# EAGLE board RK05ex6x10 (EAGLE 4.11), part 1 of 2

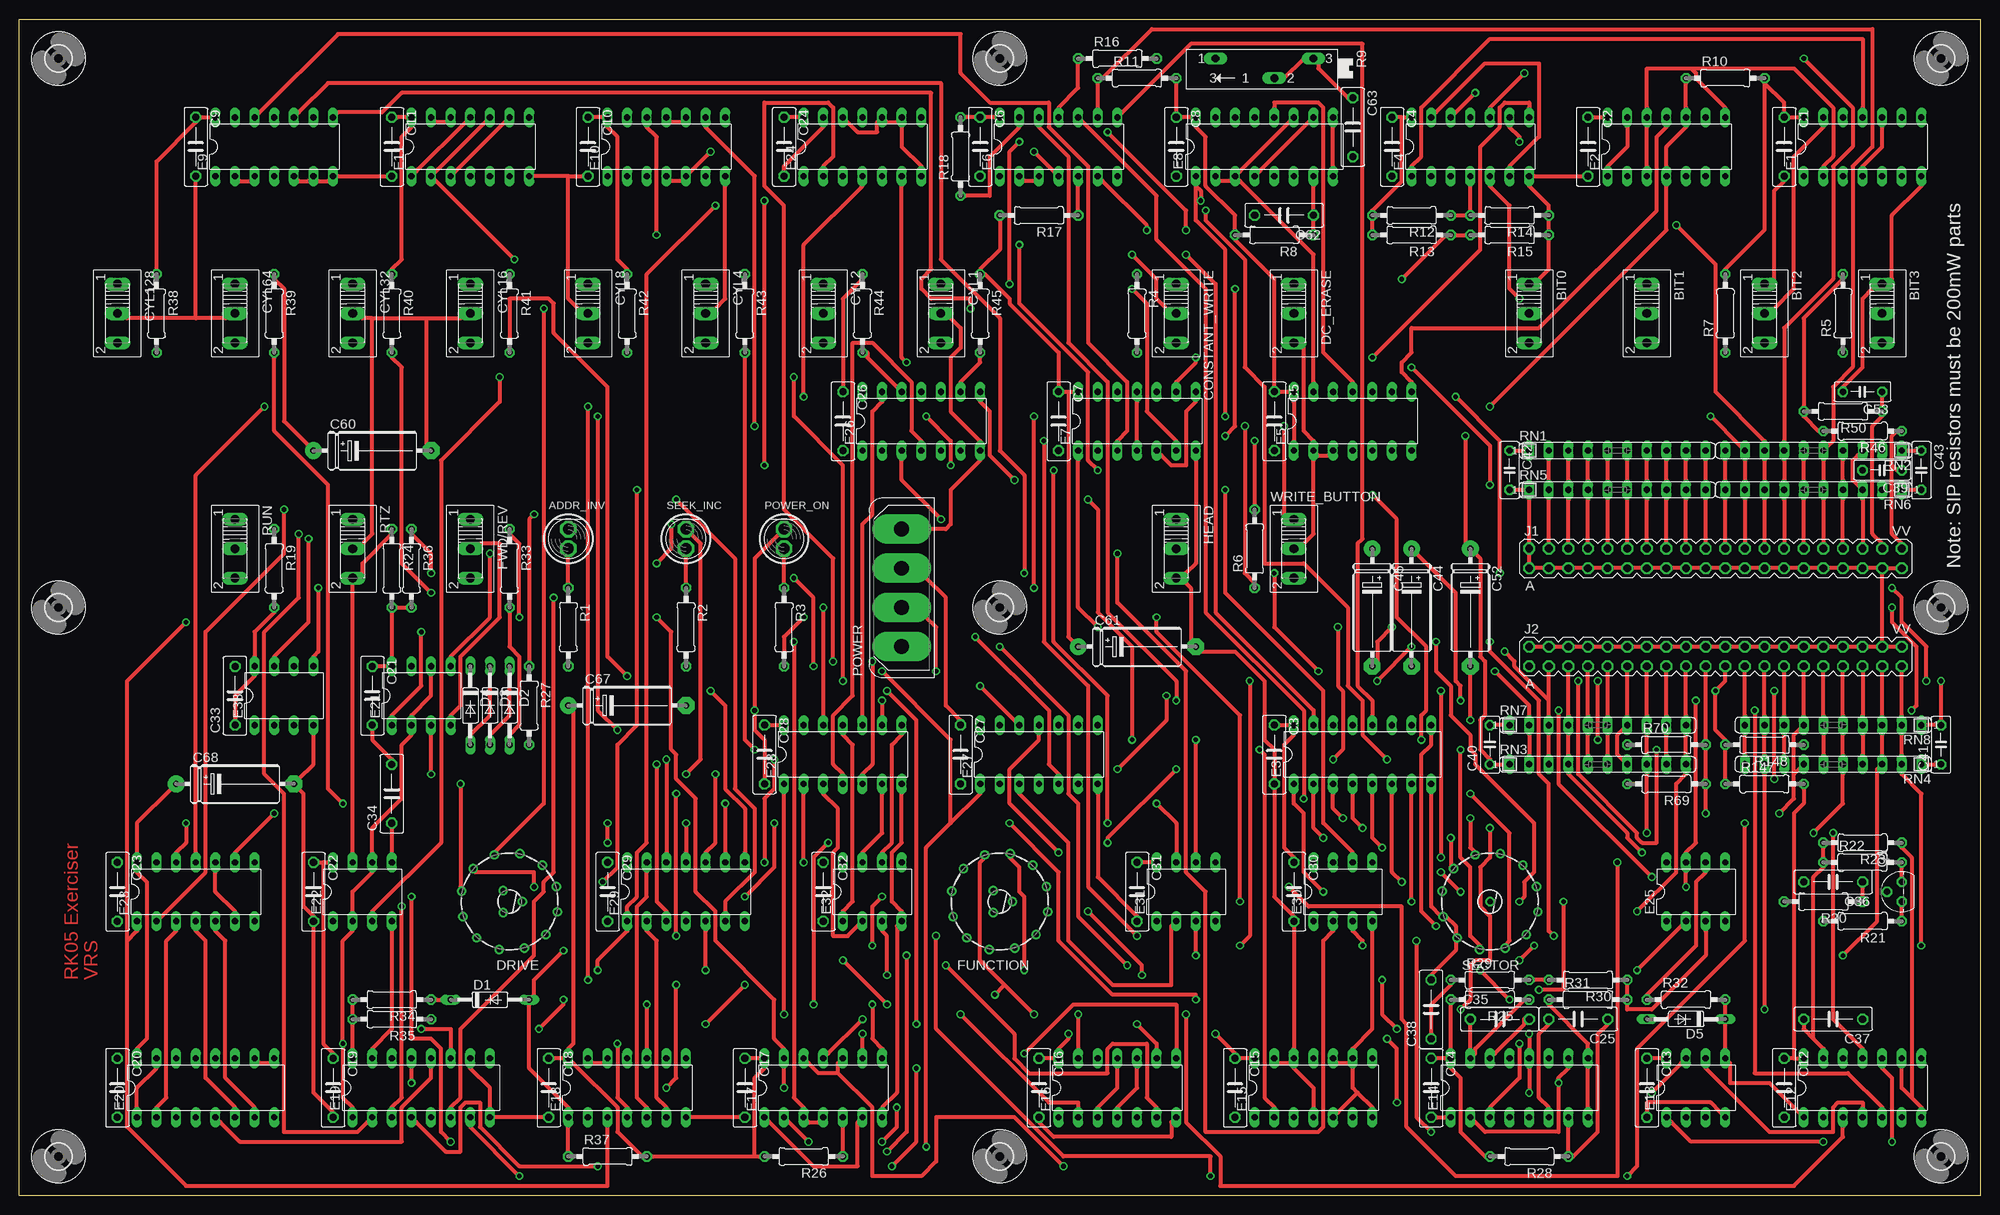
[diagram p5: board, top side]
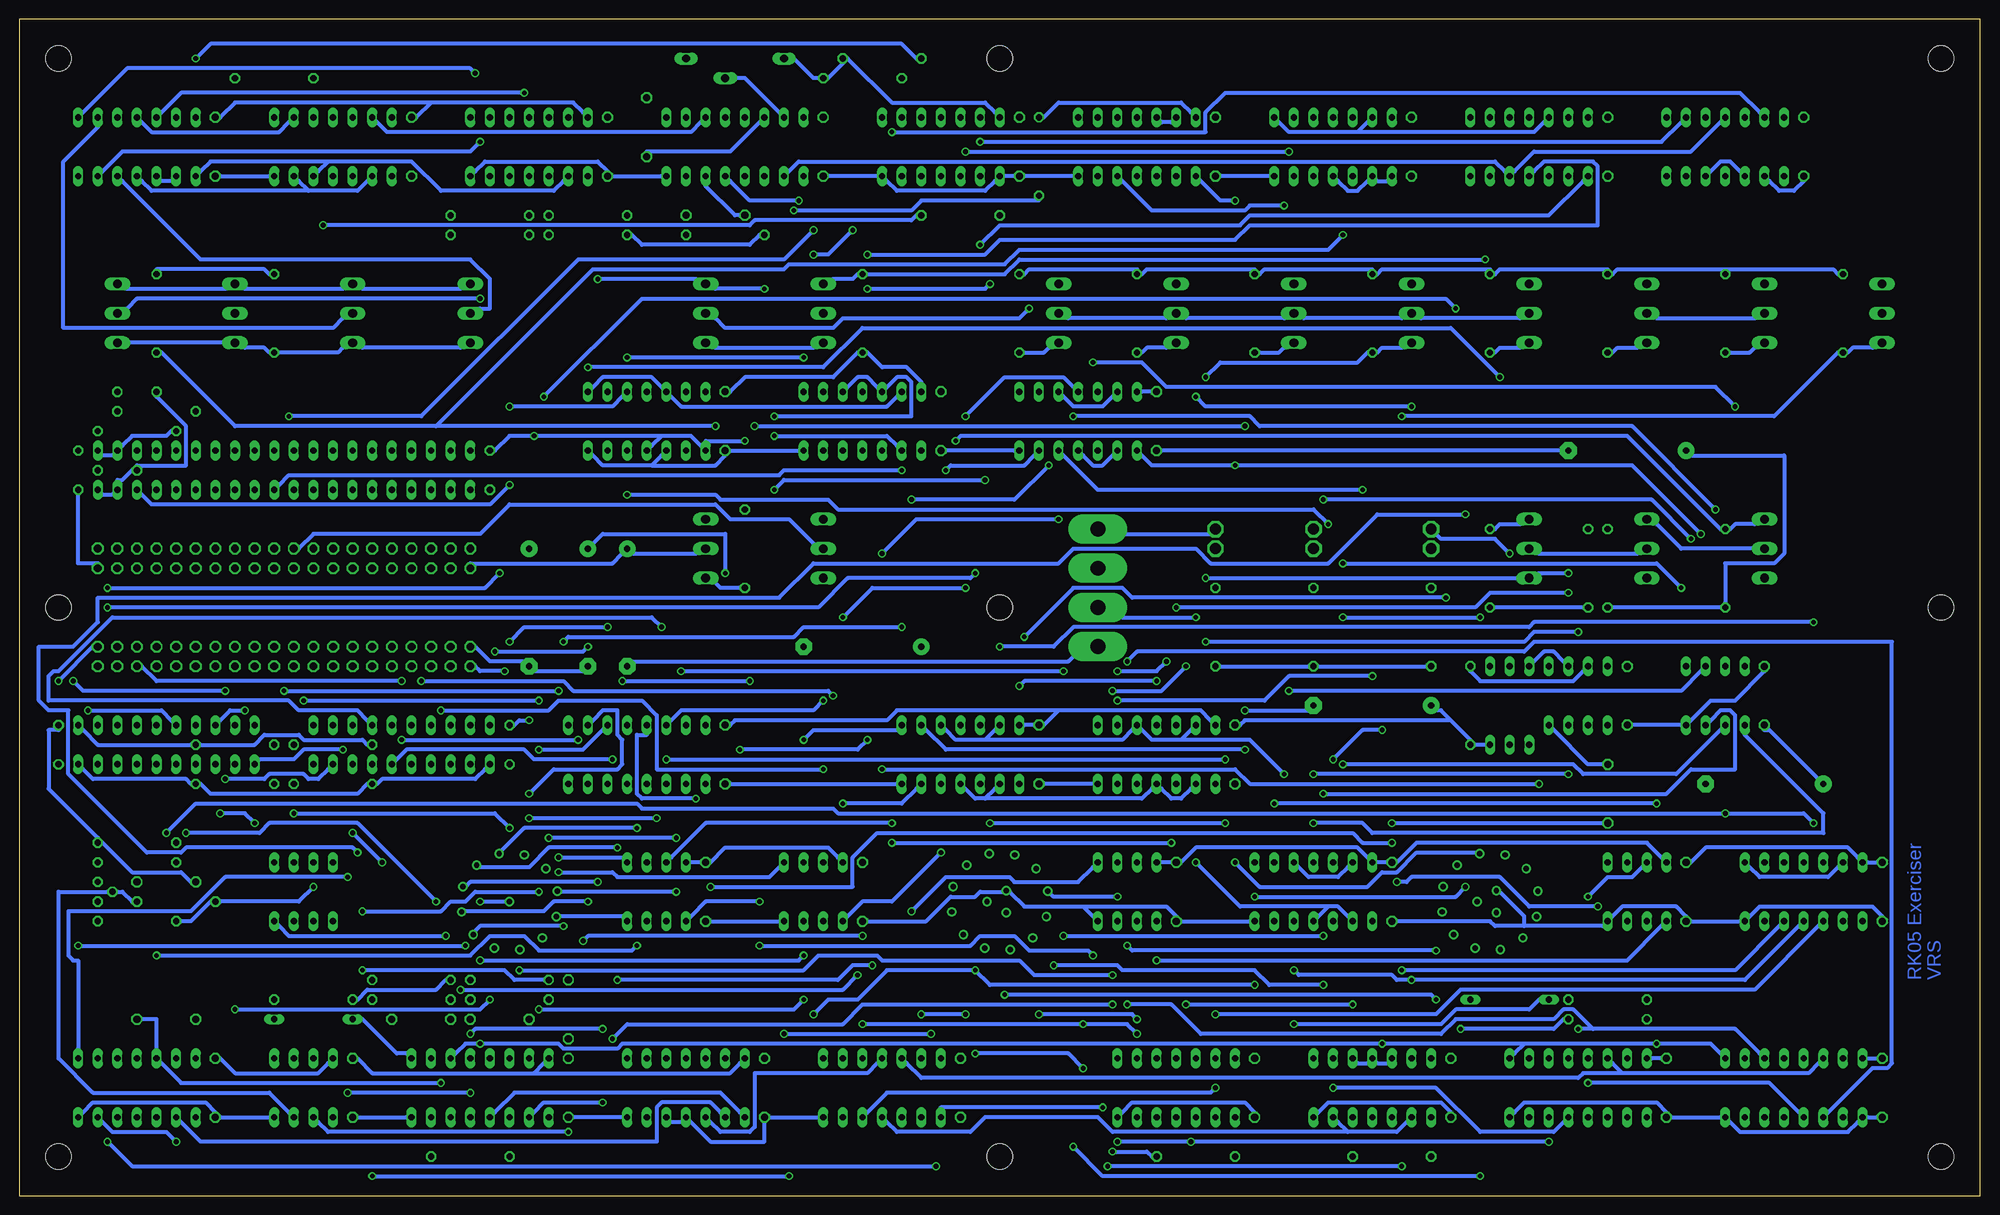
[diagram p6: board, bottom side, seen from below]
Size 254 x 152.4 mm. Coordinates in mm from the lower left corner, seen from the top.
Outline: 0,0 0,152.4 254,152.4 254,0 0,0
Copper layers (1*16): Top 0.035mm / dielectric 1.5mm / Bottom 0.035mm
Design rules "10mils": minimum track width 10mil, minimum drill 24mil, track to track 10mil, track to pad 10mil, pad to pad 10mil, via to via 10mil, smd to smd 10mil, copper to edge 25mil, drill to drill 10mil, minimum pad ring 10mil, minimum via ring 8mil, stop-mask expansion 0mil, vias tented up to drill 0mil, thermal gap 10mil
Net classes: 0 default: width 0.508 mm, drill 0.279 mm

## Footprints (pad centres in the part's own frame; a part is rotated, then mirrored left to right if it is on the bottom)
BULB = drill 1.422 octagon: A 0,0; B 0,2.54
255SB = drill 1.118 long: 1 -3.81,0; 2 0,0; 3 3.81,0
C075-032X103 = drill 0.914 octagon: 1 -3.81,0; 2 3.81,0
C050-025X075 = drill 0.813 octagon: 1 -2.54,0; 2 2.54,0
E15-5 = drill 0.813 pad 2.159 round: + -7.62,0 | drill 0.813 pad 2.159 octagon: - 7.62,0
DO35-10 = drill 0.813 long: A 5.08,0; C -5.08,0
DO35Z10 = drill 0.813 long: A 5.08,0; C -5.08,0
50-3POLE30 = drill 0.7 pad 1.2 round: 1 6.207,-1.342; 2 4.704,-4.265; 3 1.941,-6.046; 4 -1.342,-6.207; 5 -4.265,-4.704; 6 -6.046,-1.941; 7 -6.207,1.342; 8 -4.704,4.265; 9 -1.941,6.046; 10 1.342,6.207; 11 4.265,4.704; 12 6.046,1.941; C1 0.825,-1.429; C2 -1.65,0; C3 0.825,1.429
DIL14 = drill 0.813 long: 1 -7.62,-3.81; 2 -5.08,-3.81; 3 -2.54,-3.81; 4 0,-3.81; 5 2.54,-3.81; 6 5.08,-3.81; 7 7.62,-3.81; 8 7.62,3.81; 9 5.08,3.81; 10 2.54,3.81; 11 0,3.81; 12 -2.54,3.81; 13 -5.08,3.81; 14 -7.62,3.81
DIL16 = drill 0.813 long: 1 -8.89,-3.81; 2 -6.35,-3.81; 3 -3.81,-3.81; 4 -1.27,-3.81; 5 1.27,-3.81; 6 3.81,-3.81; 7 6.35,-3.81; 8 8.89,-3.81; 9 8.89,3.81; 10 6.35,3.81; 11 3.81,3.81; 12 1.27,3.81; 13 -1.27,3.81; 14 -3.81,3.81; 15 -6.35,3.81; 16 -8.89,3.81
DIL08 = drill 0.813 long: 1 -3.81,-3.81; 2 -1.27,-3.81; 3 1.27,-3.81; 4 3.81,-3.81; 5 3.81,3.81; 6 1.27,3.81; 7 -1.27,3.81; 8 -3.81,3.81
DEC40PINV = drill 1.016 octagon: A -24.13,-1.27; AA 3.81,-1.27; B -24.13,1.27; BB 3.81,1.27; C -21.59,-1.27; CC 6.35,-1.27; D -21.59,1.27; DD 6.35,1.27; E -19.05,-1.27; EE 8.89,-1.27; F -19.05,1.27; FF 8.89,1.27; H -16.51,-1.27; HH 11.43,-1.27; J -16.51,1.27; JJ 11.43,1.27; K -13.97,-1.27; KK 13.97,-1.27; L -13.97,1.27; LL 13.97,1.27; M -11.43,-1.27; MM 16.51,-1.27; N -11.43,1.27; NN 16.51,1.27; P -8.89,-1.27; PP 19.05,-1.27; R -8.89,1.27; RR 19.05,1.27; S -6.35,-1.27; SS 21.59,-1.27; T -6.35,1.27; TT 21.59,1.27; U -3.81,-1.27; UU 24.13,-1.27; V -3.81,1.27; VV 24.13,1.27; W -1.27,-1.27; X -1.27,1.27; Y 1.27,-1.27; Z 1.27,1.27
FLOPPY-4 = drill 1.93 pad 3.81 long: 1 7.62,0; 2 2.54,0; 3 -2.54,0; 4 -7.62,0
TO92E = drill 0.813 octagon: B1 -1.27,0; B2 1.27,0; E 0,1.905
0207/10 = drill 0.813 octagon: 1 -5.08,0; 2 5.08,0
SP19L = drill 1.016 long: A 5.715,-1.27; E -6.985,-1.27; S -1.905,1.27
SIL10 = drill 0.813 long: 1 -11.43,0; 2 -8.89,0; 3 -6.35,0; 4 -3.81,0; 5 -1.27,0; 6 1.27,0; 7 3.81,0; 8 6.35,0; 9 8.89,0; 10 11.43,0
50-1POLE30 = drill 0.7 pad 1.2 round: 1 6.207,-1.342; 2 4.704,-4.265; 3 1.941,-6.046; 4 -1.342,-6.207; 5 -4.265,-4.704; 6 -6.046,-1.941; 7 -6.207,1.342; 8 -4.704,4.265; 9 -1.941,6.046; 10 1.342,6.207; 11 4.265,4.704; 12 6.046,1.941; C 0,0
3,3 = hole 3.3: 0,0

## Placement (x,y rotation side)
ADDR_INV  [BULB]  71.12,83.82 0 top
BIT0  [255SB]  195.58,114.3 270 top
BIT1  [255SB]  210.82,114.3 270 top
BIT2  [255SB]  226.06,114.3 270 top
BIT3  [255SB]  241.3,114.3 270 top
C1  .01uf  [C075-032X103]  228.6,135.89 270 top
C2  .01uf  [C075-032X103]  203.2,135.89 270 top
C3  .01uf  [C075-032X103]  162.56,57.15 270 top
C4  .01uf  [C075-032X103]  177.8,135.89 270 top
C5  .01uf  [C075-032X103]  162.56,100.33 270 top
C6  .01uf  [C075-032X103]  124.46,135.89 270 top
C7  .01uf  [C075-032X103]  134.62,100.33 270 top
C8  .01uf  [C075-032X103]  149.86,135.89 270 top
C9  .01uf  [C075-032X103]  22.86,135.89 270 top
C10  .01uf  [C075-032X103]  73.66,135.89 270 top
C11  .01uf  [C075-032X103]  48.26,135.89 270 top
C12  .01uf  [C075-032X103]  228.6,13.97 270 top
C13  .01uf  [C075-032X103]  210.82,13.97 270 top
C14  .01uf  [C075-032X103]  182.88,13.97 270 top
C15  .01uf  [C075-032X103]  157.48,13.97 270 top
C16  .01uf  [C075-032X103]  132.08,13.97 270 top
C17  .01uf  [C075-032X103]  93.98,13.97 270 top
C18  .01uf  [C075-032X103]  68.58,13.97 270 top
C19  .01uf  [C075-032X103]  40.64,13.97 270 top
C20  .01uf  [C075-032X103]  12.7,13.97 270 top
C21  .01uf  [C075-032X103]  45.72,64.77 270 top
C22  .01uf  [C075-032X103]  38.1,39.37 270 top
C23  .01uf  [C075-032X103]  12.7,39.37 270 top
C24  .01uf  [C075-032X103]  99.06,135.89 270 top
C25  470pf  [C075-032X103]  201.93,22.86 180 top
C26  .01uf  [C075-032X103]  106.68,100.33 270 top
C27  .01uf  [C075-032X103]  121.92,57.15 270 top
C28  .01uf  [C075-032X103]  96.52,57.15 270 top
C29  .01uf  [C075-032X103]  76.2,39.37 270 top
C30  .01uf  [C075-032X103]  165.1,39.37 270 top
C31  .01uf  [C075-032X103]  144.78,39.37 270 top
C32  .01uf  [C075-032X103]  104.14,39.37 270 top
C33  .01uf  [C075-032X103]  27.94,64.77 90 top
C34  .001uf  [C075-032X103]  48.26,52.07 90 top
C35  470pf  [C075-032X103]  191.77,22.86 0 top
C36  .033uf  [C075-032X103]  234.95,40.64 180 top
C37  .001uf  [C075-032X103]  234.95,22.86 180 top
C38  100pf  [C075-032X103]  182.88,24.13 90 top
C39  .001  [C050-025X075]  241.3,93.98 180 top
C40  .22uf  [C050-025X075]  190.5,58.42 90 top
C41  .22uf  [C050-025X075]  248.92,58.42 90 top
C42  .22uf  [C050-025X075]  193.04,93.98 270 top
C43  .22uf  [C050-025X075]  246.38,93.98 270 top
C44  6.8uf  [E15-5]  180.34,76.2 270 top
C45  6.8uf  [E15-5]  175.26,76.2 270 top
C52  39uf  [E15-5]  187.96,76.2 270 top
C53  .001  [C050-025X075]  238.76,104.14 180 top
C60  6.8uf  [E15-5]  45.72,96.52 0 top
C61  6.8uf  [E15-5]  144.78,71.12 0 top
C62  27pf  [C075-032X103]  163.83,127 180 top
C63  47pf  [C075-032X103]  172.72,138.43 270 top
C67  6.8uf  [E15-5]  78.74,63.5 0 top
C68  6.8uf  [E15-5]  27.94,53.34 0 top
CONSTANT_WRITE  [255SB]  149.86,114.3 270 top
CYL1  [255SB]  119.38,114.3 270 top
CYL2  [255SB]  104.14,114.3 270 top
CYL4  [255SB]  88.9,114.3 270 top
CYL8  [255SB]  73.66,114.3 270 top
CYL16  [255SB]  58.42,114.3 270 top
CYL32  [255SB]  43.18,114.3 270 top
CYL64  [255SB]  27.94,114.3 270 top
CYL128  [255SB]  12.7,114.3 270 top
D1  D664  [DO35-10]  60.96,25.4 0 top
D2  D664  [DO35-10]  63.5,63.5 270 top
D3  D664  [DO35-10]  60.96,63.5 270 top
D4  D664  [DO35-10]  58.42,63.5 270 top
D5  1N746  [DO35Z10]  215.9,22.86 180 top
DC_ERASE  [255SB]  165.1,114.3 270 top
DRIVE  50-3POLE30  [50-3POLE30]  63.5,38.1 180 top
E1  74LS10N  [DIL14]  238.76,135.89 0 top
E2  74LS74N  [DIL14]  213.36,135.89 0 top
E3  74LS42N  [DIL16]  173.99,57.15 0 top
E4  74LS20N  [DIL14]  187.96,135.89 0 top
E5  74LS74N  [DIL14]  172.72,100.33 0 top
E6  74LS04N  [DIL14]  134.62,135.89 0 top
E7  74LS00N  [DIL14]  144.78,100.33 0 top
E8  74123N  [DIL16]  161.29,135.89 0 top
E9  DS8881N  [DIL14]  33.02,135.89 0 top
E10  74LS00N  [DIL14]  83.82,135.89 0 top
E11  74LS74N  [DIL14]  58.42,135.89 0 top
E12  74LS04N  [DIL14]  238.76,13.97 0 top
E13  DS75451N  [DIL08]  217.17,13.97 0 top
E14  74123N  [DIL16]  194.31,13.97 0 top
E15  74LS00N  [DIL14]  167.64,13.97 0 top
E16  74LS10N  [DIL14]  142.24,13.97 0 top
E17  74LS00N  [DIL14]  104.14,13.97 0 top
E18  74LS74N  [DIL14]  78.74,13.97 0 top
E19  74LS193N  [DIL16]  52.07,13.97 0 top
E20  74LS193N  [DIL16]  24.13,13.97 0 top
E21  DS75451N  [DIL08]  52.07,64.77 0 top
E22  DS75451N  [DIL08]  44.45,39.37 0 top
E23  74LS10N  [DIL14]  22.86,39.37 0 top
E24  74LS20N  [DIL14]  109.22,135.89 0 top
E25  LM741P  [DIL08]  217.17,39.37 0 top
E26  74LS00N  [DIL14]  116.84,100.33 0 top
E27  74LS00N  [DIL14]  132.08,57.15 0 top
E28  74LS00N  [DIL14]  106.68,57.15 0 top
E29  74LS00N  [DIL14]  86.36,39.37 0 top
E30  DS75451N  [DIL08]  171.45,39.37 0 top
E31  DS75451N  [DIL08]  151.13,39.37 0 top
E32  DS75451N  [DIL08]  110.49,39.37 0 top
E33  DS75451N  [DIL08]  34.29,64.77 0 top
FUNCTION  50-3POLE30  [50-3POLE30]  127,38.1 180 top
FWD/REV  [255SB]  58.42,83.82 270 top
HEAD  [255SB]  149.86,83.82 270 top
IC1  OPA1013P  [DIL08]  not placed on the board
J1  DEC40PINSV  [DEC40PINV]  219.71,82.55 0 top
J2  DEC40PINSV  [DEC40PINV]  219.71,69.85 0 top
POWER  [FLOPPY-4]  114.3,78.74 90 top
POWER_ON  [BULB]  99.06,83.82 0 top
Q1  2N4894  [TO92E]  243.84,39.37 90 top
R1  0ohm  [0207/10]  71.12,73.66 270 top
R2  0ohm  [0207/10]  86.36,73.66 270 top
R3  0ohm  [0207/10]  99.06,73.66 270 top
R4  1K  [0207/10]  144.78,114.3 270 top
R5  56K  [0207/10]  236.22,114.3 90 top
R6  56K  [0207/10]  160.02,83.82 90 top
R7  1K  [0207/10]  220.98,114.3 90 top
R8  5.6k  [0207/10]  162.56,124.46 180 top
R9  10K  [SP19L]  160.66,146.05 180 top
R10  1K  [0207/10]  220.98,144.78 0 top
R11  1K  [0207/10]  144.78,144.78 0 top
R12  330  [0207/10]  180.34,127 180 top
R13  330  [0207/10]  180.34,124.46 180 top
R14  750  [0207/10]  193.04,127 180 top
R15  750  [0207/10]  193.04,124.46 180 top
R16  1K  [0207/10]  142.24,147.32 0 top
R17  1K  [0207/10]  132.08,127 180 top
R18  1K  [0207/10]  121.92,134.62 90 top
R19  1K  [0207/10]  33.02,81.28 270 top
R20  470K  [0207/10]  233.68,38.1 180 top
R21  330  [0207/10]  238.76,35.56 180 top
R22  120  [0207/10]  238.76,43.18 0 top
R23  68  [0207/10]  238.76,45.72 180 top
R24  1K  [0207/10]  48.26,81.28 270 top
R25  10K  [0207/10]  190.5,25.4 180 top
R26  1K  [0207/10]  101.6,5.08 180 top
R27  1K  [0207/10]  66.04,63.5 270 top
R28  22K  [0207/10]  195.58,5.08 180 top
R29  100K  [0207/10]  190.5,27.94 0 top
R30  100K  [0207/10]  203.2,27.94 180 top
R31  1M  [0207/10]  203.2,25.4 0 top
R32  1K  [0207/10]  215.9,25.4 0 top
R33  1K  [0207/10]  63.5,81.28 270 top
R34  1K  [0207/10]  48.26,25.4 180 top
R35  1K  [0207/10]  48.26,22.86 180 top
R36  1K  [0207/10]  50.8,81.28 270 top
R37  1K  [0207/10]  76.2,5.08 0 top
R38  1K  [0207/10]  17.78,114.3 270 top
R39  1K  [0207/10]  33.02,114.3 270 top
R40  1K  [0207/10]  48.26,114.3 270 top
R41  1K  [0207/10]  63.5,114.3 270 top
R42  1K  [0207/10]  78.74,114.3 270 top
R43  1K  [0207/10]  93.98,114.3 270 top
R44  1K  [0207/10]  109.22,114.3 270 top
R45  1K  [0207/10]  124.46,114.3 270 top
R46  390  [0207/10]  238.76,99.06 180 top
R50  390  [0207/10]  236.22,101.6 180 top
R69  180  [0207/10]  213.36,53.34 180 top
R70  390  [0207/10]  213.36,58.42 0 top
R147  180  [0207/10]  226.06,53.34 0 top
R148  390  [0207/10]  226.06,58.42 180 top
RN1  180  [SIL10]  207.01,96.52 0 top
RN2  180  [SIL10]  232.41,96.52 180 top
RN3  180  [SIL10]  204.47,55.88 0 top
RN4  180  [SIL10]  234.95,55.88 180 top
RN5  390  [SIL10]  207.01,91.44 0 top
RN6  390  [SIL10]  232.41,91.44 180 top
RN7  390  [SIL10]  204.47,60.96 0 top
RN8  390  [SIL10]  234.95,60.96 180 top
RTZ  [255SB]  43.18,83.82 270 top
RUN  [255SB]  27.94,83.82 270 top
SECTOR  50-1POLE30  [50-1POLE30]  190.5,38.1 180 top
SEEK_INC  [BULB]  86.36,83.82 0 top
U$1  [3,3]  5.08,147.32 0 top
U$2  [3,3]  5.08,5.08 0 top
U$3  [3,3]  5.08,76.2 0 top
U$4  [3,3]  248.92,147.32 0 top
U$5  [3,3]  248.92,5.08 0 top
U$6  [3,3]  248.92,76.2 0 top
U$7  [3,3]  127,147.32 0 top
U$8  [3,3]  127,5.08 0 top
U$9  [3,3]  127,76.2 0 top
WRITE_BUTTON  MOM  [255SB]  165.1,83.82 270 top

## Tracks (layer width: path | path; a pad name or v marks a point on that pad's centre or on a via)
0BIT  (via drill 0.61)
  Top 0.508: v194.31,136.53 194.31,137.16 193.04,138.43 E4.9
  Bottom 0.508: v194.31,136.53 195.58,135.25 240.66,135.25 243.21,132.72 E1.6
1.44MHZ
  Top 0.508: E5.11 172.72,105.41 168.91,109.22 168.91,140.97 168.28,141.6 162.56,141.6 162.56,140.97 E8.12
1BIT  (via drill 0.61)
  Top 0.508: v194.94,145.41 190.5,140.97 E4.10
  Bottom 0.508: v194.94,145.41 195.58,146.05 240.03,146.05 245.75,140.34 E1.8
1L
  Top 0.508: E2.11 213.36,138.43 212.09,137.16 212.09,127.64 196.85,112.39 180.34,112.39 180.34,109.22 179.07,107.95 179.07,106.68 180.34,105.41 E5.8
  Bottom 0.508: E7.13 140.34,103.5 141.6,102.23 168.28,102.23 169.54,103.5 E5.12 170.81,104.78 172.09,106.05 178.44,106.05 179.71,104.78 E5.8
2.88MHZ
  Top 0.508: E8.4 160.66,132.72 167,139.06 E8.10
2BIT  (via drill 0.61)
  Top 0.508: v188.59,142.88 186.06,140.34 E4.12
  Bottom 0.508: v188.59,142.88 233.04,142.88 235.59,140.34 E1.12
2H
  Top 0.508: E4.1 180.34,133.35 181.61,134.62 181.61,140.97 190.5,149.86 238.76,149.86 238.76,140.97 E1.11
  Bottom 0.508: E2.9 219.07,139.06 220.34,137.79 236.85,137.79 238.12,139.06 E1.11
2L
  Top 0.508: E2.3 210.82,133.35 210.82,138.43 E2.12 210.82,140.97 210.82,146.05 216.53,146.05 | 216.53,146.05 217.17,145.41 217.17,144.78 220.98,140.97 E2.8 | 216.53,146.05 229.87,146.05 234.95,140.97 234.95,134.62 233.68,133.35 E1.2
  Bottom 0.508: E1.2 234.31,131.44 235.59,131.44 E1.3
3BIT
  Top 0.508: E4.13 183.51,140.34 189.87,146.69 196.85,146.69 196.85,137.16 193.04,133.35 E4.6
4H
  Bottom 0.508: 214,133.99 203.2,133.99 199.39,130.18 184.78,130.18 183.51,131.44 E4.2 | 214,133.99 215.26,132.72 E2.5 | 214,133.99 229.24,133.99 230.5,132.72 E1.1
4L
  Top 0.508: E1.4 238.76,133.35 241.3,135.89 241.3,138.43 E1.10
  Bottom 0.508: 216.53,130.18 210.19,130.18 208.91,131.44 E2.2 | 216.53,130.18 217.81,131.44 E2.6 | 216.53,130.18 236.85,130.18 238.12,131.44 E1.4
202_DETECT_L  (via drill 0.61)
  Top 0.508: v31.75,102.23 22.86,93.34 22.86,44.45 E23.11 | v114.94,107.95 114.3,108.58 114.3,130.81 E24.6
  Bottom 0.508: v31.75,102.23 34.29,104.78 105.41,104.78 108.58,107.95 v114.94,107.95
+3V  (via drill 0.61)
  Top 0.508: E21.6 53.34,67.31 53.34,64.77 50.8,62.23 E21.2 50.8,59.69 49.53,58.42 49.53,51.44 45.72,47.62 45.72,44.45 E22.6 45.72,41.91 43.18,39.37 43.18,36.83 E22.2 43.18,34.29 41.91,33.02 v41.91,19.68 41.91,12.7 43.18,11.43 E19.1 | v194.31,19.68 194.31,15.24 190.5,11.43 E14.3 | E20.10 31.11,17.14 32.38,17.14 E20.9 | v77.47,19.68 77.47,12.7 78.74,11.43 E18.4
  Bottom 0.508: D4.C 57.78,69.22 56.52,70.48 55.24,70.48 53.98,69.22 E21.6 | E14.11 197.49,18.41 196.22,19.68 v194.31,19.68 184.15,19.68 183.51,19.05 176.53,19.05 175.9,19.68 v77.47,19.68 59.05,19.68 | 59.05,19.68 60.33,18.41 E19.9 | 59.05,19.68 v41.91,19.68 34.92,19.68 33.66,18.41 E20.9
+3VA  (via drill 0.61)
  Top 0.508: R15.2 187.32,124.46 186.06,124.46 R13.1 184.78,124.46 v179.07,118.75 | v156.21,98.42 157.48,99.69 v157.48,117.47
  Bottom 0.508: v156.21,98.42 141.6,98.42 140.34,97.16 E7.2 | v157.48,117.47 163.83,117.47 DC_ERASE.1 166.37,118.75 v179.07,118.75
+3VB
  Top 0.508: R12.1 186.06,127 187.32,127 R14.2 187.96,127.64 187.96,130.81 E4.4
+3VC  (via drill 0.61)
  Top 0.508: E11.10 60.33,139.06 53.98,132.72 E11.2 53.98,131.44 v64.14,121.28
  Bottom 0.508: CONSTANT_WRITE.1 148.59,118.75 146.05,118.75 145.41,119.38 R4.1 144.15,119.38 126.36,119.38 124.46,121.28 v64.14,121.28
+15V  (via drill 0.61)
  Top 0.508: v101.6,74.93 99.06,72.39 99.06,69.22 R3.2 | v215.9,40.01 215.9,41.91 E25.7 215.9,44.45 217.17,45.72 v217.17,64.14 | v186.69,64.14 186.69,66.04 186.06,66.67 186.06,78.11 180.97,83.19 C44.+ | v118.75,67.94 118.75,73.66 117.47,74.93 POWER.3 | v168.28,67.94 162.56,73.66 v162.56,80.64
  Bottom 0.508: R1.2 71.75,68.58 85.72,68.58 R2.2 87,68.58 98.42,68.58 R3.2 | v101.6,74.93 111.12,74.93 POWER.3 | R21.2 233.04,35.56 231.78,35.56 229.24,38.1 R20.2 227.97,38.1 217.81,38.1 v215.9,40.01 | v217.17,64.14 v186.69,64.14 | v168.28,67.94 v118.75,67.94 | v162.56,80.64 162.56,85.72 178.44,85.72 179.71,84.45 C44.+
-15V  (via drill 0.61)
  Top 0.508: v198.75,33.66 198.12,34.29 198.12,53.34 196.85,54.61 196.85,64.14 190.5,70.48 v190.5,71.75 | v177.8,73.66 175.9,71.75 175.9,69.22 C45.-
  Bottom 0.508: v198.75,33.66 219.07,33.66 220.34,34.92 E25.4 | v190.5,71.75 188.59,73.66 v177.8,73.66 | POWER.4 117.47,69.85 118.11,69.22 174.62,69.22 C45.-
ADDR_COUNTER_1  (via drill 0.61)
  Top 0.508: v49.53,37.47 49.53,12.7 48.26,11.43 E19.3 | v75.56,40.64 77.47,42.55 77.47,58.42 80.01,60.96 v80.01,91.44
  Bottom 0.508: v49.53,37.47 58.42,37.47 62.23,41.27 73.66,41.27 74.3,40.64 v75.56,40.64 | v80.01,91.44 114.3,91.44 118.75,95.89 E26.5
ADDR_COUNTER_2  (via drill 0.61)
  Top 0.508: v36.2,85.72 36.2,77.47 31.75,73.03 31.75,54.61 34.29,52.07 34.29,8.26 43.81,8.26 45.09,9.53 E19.2 | v96.52,94.61 v96.52,128.91
  Bottom 0.508: v36.2,85.72 45.09,94.61 v96.52,94.61 107.31,94.61 108.58,95.89 E26.1 | v96.52,128.91 98.42,128.91 100.97,131.44 E24.1
ADDR_COUNTER_4  (via drill 0.61)
  Top 0.508: v69.22,77.47 69.22,41.91 67.94,40.64 67.94,39.37 66.67,38.1 66.67,31.11 57.15,21.59 57.15,12.7 55.88,11.43 E19.6 | v123.83,72.39 133.35,62.87 133.35,55.88 134.62,54.61 E27.5
  Bottom 0.508: v69.22,77.47 109.86,77.47 111.12,78.74 117.47,78.74 v123.83,72.39
ADDR_COUNTER_8  (via drill 0.61)
  Top 0.508: v64.77,2.54 58.42,8.89 E19.7 | v117.47,6.35 117.47,45.09 120.65,48.26 | 120.65,48.26 124.46,52.07 E27.1 | v105.41,69.22 105.41,82.55 99.06,88.9 99.06,128.27 96.52,130.81 96.52,141.6 104.78,141.6 105.41,140.97 105.41,134.62 104.14,133.35 E24.2 | v111.76,67.94 120.65,59.05 120.65,48.26
  Bottom 0.508: v64.77,2.54 113.67,2.54 v117.47,6.35 | v105.41,69.22 106.68,67.94 v111.76,67.94
ADDR_COUNTER_16  (via drill 0.61)
  Top 0.508: v110.49,69.22 110.49,55.88 109.22,54.61 E28.5
  Bottom 0.508: v110.49,69.22 109.22,70.48 59.05,70.48 57.78,71.75 11.43,71.75 11.43,17.14 12.06,16.51 13.97,16.51 19.68,10.79 E20.3
ADDR_COUNTER_32  (via drill 0.61)
  Top 0.508: E20.2 17.78,11.43 19.05,12.7 19.05,33.02 20.32,34.29 E23.3 | v99.06,23.5 99.06,52.07 E28.1
  Bottom 0.508: v99.06,23.5 70.48,23.5 67.31,26.67 29.21,26.67 20.95,34.92 E23.3
ADDR_COUNTER_64  (via drill 0.61)
  Top 0.508: E20.6 27.94,11.43 24.13,15.24 24.13,33.02 22.86,34.29 E23.4 | v88.9,29.21 88.9,34.29 E29.5 | v101.6,103.5 101.6,123.19 109.22,130.81 E24.4 | v73.66,27.94 v73.66,102.23
  Bottom 0.508: v88.9,29.21 88.27,28.57 76.2,28.57 75.56,27.94 v73.66,27.94 30.48,27.94 23.5,34.92 E23.4 | v101.6,103.5 100.33,102.23 v73.66,102.23
ADDR_COUNTER_128  (via drill 0.61)
  Top 0.508: E20.7 30.48,11.43 26.67,15.24 26.67,33.02 25.4,34.29 E23.5 | v74.93,29.21 74.93,30.48 78.74,34.29 E29.1 78.74,36.83 78.74,37.47 80.01,38.73 80.01,44.45 81.28,45.72 81.28,119.38 v90.17,128.27
  Bottom 0.508: v74.93,29.21 31.75,29.21 26.04,34.92 E23.5 | v90.17,128.27 94.61,128.27 95.25,127.64 107.31,127.64 111.12,131.44 E24.5
ADDR_SOURCE_H  (via drill 0.61)
  Top 0.508: E18.5 81.28,11.43 80.01,12.7 80.01,37.47 81.28,38.73 81.28,41.91 E29.13 | E26.13 111.76,102.87 110.49,101.6 110.49,88.27 109.22,87 109.22,62.23 E28.10 | v90.17,54.61 90.17,45.72 88.9,44.45 E29.10
  Bottom 0.508: E29.10 88.27,42.55 87,41.27 83.19,41.27 81.92,42.55 E29.13 | E26.13 112.39,103.5 113.67,102.23 117.47,102.23 118.75,103.5 E26.10 | 103.5,59.05 102.23,60.33 E28.13 | 103.5,59.05 107.31,59.05 108.58,60.33 E28.10 109.86,60.33 111.12,59.05 128.91,59.05 | 128.91,59.05 127.64,60.33 E27.13 | 128.91,59.05 132.72,59.05 133.99,60.33 E27.10 | v90.17,54.61 94.61,59.05 103.5,59.05
ADDR_SOURCE_L  (via drill 0.61)
  Top 0.508: E26.4 116.84,97.79 115.57,99.06 115.57,105.41 110.49,110.49 107.95,110.49 107.95,64.77 105.41,62.23 105.41,55.88 106.68,54.61 E28.4 | E16.4 142.24,11.43 144.78,13.97 144.78,16.51 E16.10 | E29.2 81.28,34.29 82.55,33.02 82.55,12.7 83.82,11.43 E18.6 | v101.6,43.18 101.6,52.07 E28.2
  Bottom 0.508: E26.2 112.39,95.89 113.67,94.61 114.94,94.61 116.2,95.89 E26.4 | E28.2 102.23,52.7 103.5,51.44 104.78,51.44 106.05,52.7 E28.4 107.31,52.7 108.58,51.44 128.91,51.44 | 128.91,51.44 127.64,52.7 E27.2 | 128.91,51.44 130.18,51.44 131.44,52.7 E27.4 | 84.45,37.47 83.19,37.47 81.92,36.2 E29.2 | 84.45,37.47 85.72,36.2 E29.4 | 81.92,8.26 75.56,8.26 74.3,9.53 E18.2 | 81.92,8.26 83.19,9.53 E18.6 | 81.92,8.26 112.39,8.26 114.3,10.16 128.91,10.16 130.81,8.26 140.34,8.26 141.6,9.53 E16.4 | v101.6,43.18 95.89,37.47 84.45,37.47
ADDRESS_INVALID_L  (via drill 0.61)
  Top 0.508: v60.96,83.19 60.96,74.93 55.88,69.85 E21.5
  Bottom 0.508: v60.96,83.19 62.87,85.09 69.85,85.09 70.48,85.72 ADDR_INV.B
BIT_0L
  Bottom 0.508: E1.5 240.66,131.44 230.5,121.28 195.58,121.28 193.04,118.75 193.04,114.94 194.31,114.94 BIT0.2
BIT_1L
  Bottom 0.508: E1.9 243.84,138.43 248.28,133.99 248.28,112.39 213.36,112.39 212.09,113.67 BIT1.2
BIT_2L
  Top 0.508: E1.13 233.68,138.43 229.87,134.62 229.87,117.47 227.33,114.94 BIT2.2
BIT_3L  (via drill 0.61)
  Top 0.508: v194.31,116.2 193.04,117.47 193.04,128.27 190.5,130.81 E4.5
  Bottom 0.508: v194.31,116.2 238.76,116.2 240.03,114.94 BIT3.2
BUS_AC_LO_L
  Top 0.508: 242.57,94.61 243.21,93.98 C39.1 | 242.57,94.61 242.57,98.42 243.21,99.06 R46.1 | 242.57,94.61 242.57,85.72 243.84,84.45 J1.VV
BUS_ADDR_ACCEPTED_L
  Top 0.508: RN3.5 203.2,57.15 203.2,59.69 RN7.5 203.2,62.23 203.2,67.94 J2.H
BUS_ADDRESS_INVALID_L  (via drill 0.61)
  Top 0.508: R26.1 106.68,5.71 106.68,8.89 E17.5 | RN3.3 198.12,57.15 198.12,59.69 RN7.3 198.12,62.23 198.12,64.14 | 198.12,64.14 198.12,67.94 J2.C | v112.39,5.71 114.94,8.26 v114.94,31.11 | v158.12,32.38 159.38,33.66 v159.38,66.67 | v180.34,71.12 v175.9,66.67 | v192.41,70.48 193.68,69.22 193.68,68.58 198.12,64.14
  Bottom 0.508: v112.39,5.71 107.95,5.71 107.31,5.08 R26.1 | v114.94,31.11 115.57,31.75 123.19,31.75 125.09,33.66 129.54,33.66 130.81,32.38 v158.12,32.38 | v175.9,66.67 v159.38,66.67 | v180.34,71.12 180.97,70.48 v192.41,70.48
BUS_CA_00_L  (via drill 0.61)
  Top 0.508: R147.1 220.98,53.98 220.98,57.78 R148.2 220.98,59.05 219.71,60.33 v219.71,65.41 220.98,66.67 220.98,67.94 J2.Y | v184.15,65.41 v184.15,43.81
  Bottom 0.508: v184.15,43.81 175.9,43.81 E30.5 | v219.71,65.41 v184.15,65.41
BUS_CA_01_L  (via drill 0.61)
  Top 0.508: v173.99,32.38 173.99,33.02 172.72,34.29 E30.3 | v236.22,31.11 240.66,35.56 240.66,55.24 RN4.3 241.3,57.15 241.3,59.69 RN8.3 241.3,62.23 241.3,67.94 J2.SS
  Bottom 0.508: v173.99,32.38 174.62,31.75 186.69,31.75 188.59,33.66 193.04,33.66 195.58,31.11 v236.22,31.11
BUS_CA_02_L  (via drill 0.61)
  Top 0.508: v186.69,39.37 v184.15,41.91 | v209.55,36.83 214.63,41.91 214.63,53.34 215.9,54.61 RN3.10 215.9,57.15 215.9,59.69 RN7.10 215.9,62.23 215.9,67.94 J2.U
  Bottom 0.508: v184.15,41.91 177.16,41.91 176.53,41.27 156.84,41.27 155.57,42.55 E31.5 | v186.69,39.37 194.94,39.37 196.22,38.1 198.12,38.1 199.39,36.83 v209.55,36.83
BUS_CA_03_L  (via drill 0.61)
  Top 0.508: v152.4,31.11 152.4,34.29 E31.3 | v196.22,32.38 v194.31,30.48 | v246.38,32.38 246.38,52.07 243.84,54.61 RN4.2 243.84,57.15 243.84,59.69 RN8.2 243.84,62.23 243.84,67.94 J2.UU
  Bottom 0.508: v152.4,31.11 153.03,30.48 v194.31,30.48 | v246.38,32.38 v196.22,32.38
BUS_CA_04_L  (via drill 0.61)
  Top 0.508: v138.43,36.83 145.41,29.84 v145.41,28.57 | v196.85,26.67 200.03,26.67 v200.03,38.1 | v232.41,46.99 236.22,50.8 236.22,54.61 RN4.5 236.22,57.15 236.22,59.69 RN8.5 236.22,62.23 236.22,67.94 J2.MM
  Bottom 0.508: v138.43,36.83 133.99,41.27 125.73,41.27 125.09,40.64 116.84,40.64 114.94,42.55 E32.5 | v145.41,28.57 147.32,26.67 v196.85,26.67 | v200.03,38.1 210.19,48.26 221.62,48.26 222.88,46.99 v232.41,46.99
BUS_CA_05_L  (via drill 0.61)
  Top 0.508: v112.39,28.57 112.39,33.66 111.76,34.29 E32.3 | v193.04,25.4 v189.23,29.21 | v226.06,24.13 226.06,54.61 RN4.9 226.06,57.15 226.06,59.69 RN8.9 226.06,62.23 226.06,67.94 J2.CC
  Bottom 0.508: v112.39,28.57 122.56,28.57 124.46,30.48 142.24,30.48 142.88,31.11 150.5,31.11 152.4,29.21 v189.23,29.21 | v193.04,25.4 194.31,24.13 v226.06,24.13
BUS_CA_06_L  (via drill 0.61)
  Top 0.508: RN4.4 238.76,57.15 238.76,59.69 RN8.4 238.76,62.23 238.76,67.94 J2.PP | v38.73,78.74 38.73,70.48 38.1,69.85 E33.5 | v82.55,81.92 84.45,83.82 v84.45,87 | v175.26,90.81 178.44,87.63 178.44,74.93 182.25,71.12 182.25,62.87 181.61,62.23 v181.61,59.05 | v204.47,59.05 v204.47,66.67
  Bottom 0.508: v38.73,78.74 41.91,81.92 v82.55,81.92 | v84.45,87 86.36,88.9 147.96,88.9 149.22,90.17 163.19,90.17 163.83,90.81 v175.26,90.81 | v204.47,59.05 v181.61,59.05 | v204.47,66.67 236.22,66.67 238.12,68.58 J2.PP
BUS_CA_07_L  (via drill 0.61)
  Top 0.508: J2.HH 231.14,67.94 231.14,62.23 RN8.7 230.5,60.33 229.87,59.69 229.87,54.61 | v85.09,33.66 v85.09,52.07 | v118.75,33.66 118.75,21.59 135.25,5.08 154.31,5.08 v154.31,2.54 | v208.28,2.54 209.55,3.81 209.55,19.05 223.52,33.02 v223.52,48.26 | v227.97,49.53 229.87,51.44 229.87,54.61 | 229.87,54.61 230.5,55.24 RN4.7
  Bottom 0.508: v85.09,52.07 40.64,52.07 37.47,55.24 31.75,55.24 31.75,62.23 32.38,62.87 33.66,62.87 34.92,61.59 E33.3 | v118.75,33.66 v85.09,33.66 | v208.28,2.54 v154.31,2.54 | v223.52,48.26 224.79,49.53 v227.97,49.53
BUS_DATA&CLOCK_L  (via drill 0.61)
  Top 0.508: RN4.6 233.68,57.15 233.68,59.69 RN8.6 233.68,62.23 233.68,67.94 J2.KK | v130.18,80.64 130.18,93.34 127,96.52 127,113.67 119.38,121.28 119.38,144.15 40.01,144.15 36.2,140.34 E9.10 | v242.57,76.2 242.57,74.3 245.75,71.12 245.75,63.5 v245.11,62.87
  Bottom 0.508: v130.18,80.64 130.81,80.01 146.69,80.01 150.5,76.2 v242.57,76.2 | v245.11,62.87 235.59,62.87 234.31,61.59 RN8.6
BUS_DC_LO_L
  Top 0.508: C53.1 241.3,103.5 241.3,102.23 R50.1 241.3,100.97 240.03,99.69 240.03,85.72 241.3,84.45 J1.TT
BUS_FILE_READY
  Top 0.508: RN1.9 215.9,95.25 215.9,92.71 RN5.9 215.9,90.17 215.9,84.45 J1.V
BUS_HIGH_DENSITY_L
  Top 0.508: RN1.6 208.28,95.25 208.28,92.71 RN5.6 208.28,90.17 208.28,84.45 J1.N
BUS_INDEX_L  (via drill 0.61)
  Top 0.508: RN2.10 220.98,95.25 220.98,92.71 RN6.10 220.98,90.17 220.98,84.45 J1.Z | E11.1 51.44,132.72 57.78,139.06 E11.11 | v139.7,93.98 138.43,95.25 138.43,106.68 129.54,115.57 v129.54,123.19
  Bottom 0.508: v139.7,93.98 154.94,93.98 155.57,93.34 219.07,93.34 220.34,92.08 RN6.10 | v129.54,123.19 127,125.73 95.89,125.73 94.61,127 55.88,127 51.44,131.44 E11.1
BUS_READ_GATE_L
  Top 0.508: RN1.5 205.74,95.25 205.74,92.71 RN5.5 205.74,90.17 205.74,84.45 J1.L
BUS_RESTORE_L  (via drill 0.61)
  Top 0.508: E22.5 48.26,44.45 48.26,47.62 C34.1 | J2.P 210.82,67.94 210.82,62.23 RN7.8 210.82,59.69 210.82,57.15 RN3.8 210.82,54.61 v210.82,46.99 | v76.2,45.72 v76.2,48.26 | v164.47,40.01 167,37.47 179.07,37.47 179.07,22.86 179.71,22.23 179.71,8.89 186.06,2.54 207.01,2.54 v207.01,43.18
  Bottom 0.508: v76.2,48.26 48.9,48.26 C34.1 | v76.2,45.72 80.01,45.72 81.28,46.99 142.88,46.99 146.05,43.81 146.05,40.01 v164.47,40.01 | v210.82,46.99 v207.01,43.18
BUS_RWS_READY_L  (via drill 0.61)
  Top 0.508: RN4.8 228.6,57.15 228.6,59.69 RN8.8 228.6,62.23 228.6,67.94 J2.EE | v224.79,62.87 224.79,15.88 236.85,15.88 241.3,11.43 E12.5
  Bottom 0.508: v224.79,62.87 226.69,62.87 227.97,61.59 RN8.8
BUS_SECTOR_ADDR_0L  (via drill 0.61)
  Top 0.508: R17.1 137.16,127.64 137.16,130.81 E6.5 | J1.DD 226.06,84.45 226.06,90.17 RN6.8 226.06,92.71 226.06,95.25 RN2.8 226.06,97.79 219.71,104.14 219.71,120.65 v214.63,125.73
  Bottom 0.508: v214.63,125.73 159.38,125.73 158.75,126.36 138.43,126.36 137.79,127 R17.1
BUS_SECTOR_ADDR_1L  (via drill 0.61)
  Top 0.508: RN3.6 205.74,57.15 205.74,59.69 RN7.6 205.74,62.23 205.74,67.94 J2.K | R18.1 122.56,129.54 125.73,129.54 125.73,134.62 129.54,138.43 E6.13 | v177.16,56.52 173.99,59.69 173.99,64.14 172.09,66.04 172.09,76.2 166.37,81.92 161.29,81.92 161.29,104.78 158.75,107.31 158.75,121.28 153.67,126.36 v153.67,127.64
  Bottom 0.508: v177.16,56.52 187.32,56.52 188.59,57.78 203.84,57.78 205.1,56.52 RN3.6 | v153.67,127.64 138.43,127.64 137.16,128.91 121.92,128.91 R18.1
BUS_SECTOR_ADDR_2L  (via drill 0.61)
  Top 0.508: E6.11 134.62,140.97 137.16,143.51 137.16,146.69 R16.1 | J1.FF 228.6,84.45 228.6,90.17 RN6.7 228.6,92.71 228.6,95.25 RN2.7 228.6,97.79 228.6,112.39 234.95,118.75 234.95,133.35 237.49,135.89 237.49,140.97 v231.14,147.32
  Bottom 0.508: v231.14,147.32 229.24,149.22 139.7,149.22 137.79,147.32 R16.1
BUS_SECTOR_ADDR_3L
  Top 0.508: E6.9 139.7,140.97 139.7,144.15 R11.1 140.34,144.78 146.69,151.13 240.03,151.13 240.03,135.89 237.49,133.35 237.49,107.31 234.95,104.78 234.95,97.79 234.31,97.16 RN2.5 233.68,95.25 233.68,92.71 RN6.5 233.68,90.17 233.68,84.45 J1.LL
BUS_SECTOR_PULSE_L
  Top 0.508: RN1.8 213.36,95.25 213.36,92.71 RN5.8 213.36,90.17 213.36,84.45 J1.T
BUS_SEEK_INCOMPLETE_L  (via drill 0.61)
  Top 0.508: J2.E 200.66,67.94 200.66,62.23 RN7.4 200.66,59.69 200.66,57.15 RN3.4 200.66,54.61 208.28,46.99 208.28,46.35 v210.19,44.45 | v66.67,88.27 66.04,87.63 66.04,69.22 R27.1
  Bottom 0.508: E21.7 51.44,67.94 52.7,66.67 64.77,66.67 66.04,67.94 R27.1 | v210.19,44.45 210.82,45.09 232.41,45.09 233.04,44.45 237.49,44.45 247.65,54.61 247.65,62.87 250.19,62.87 251.46,64.14 251.46,71.12 247.01,71.12 243.84,74.3 243.84,77.47 155.57,77.47 151.13,81.92 119.38,81.92 117.47,83.82 101.6,83.82 99.69,81.92 84.45,81.92 78.11,88.27 v66.67,88.27
BUS_STROBE_L  (via drill 0.61)
  Top 0.508: v62.23,106.05 62.23,102.87 54.61,95.25 54.61,45.72 45.72,36.83 E22.3 | v180.34,107.31 190.5,97.16 v190.5,92.08 | RN2.3 238.12,95.89 237.49,95.25 237.49,92.71 238.12,92.08 RN6.3 238.76,90.17 238.76,84.45 J1.RR
  Bottom 0.508: v62.23,106.05 68.58,112.39 144.78,112.39 149.86,107.31 v180.34,107.31 | v190.5,92.08 193.04,89.53 236.85,89.53 238.12,90.81 RN6.3
BUS_WP_SET_L
  Top 0.508: RN1.4 203.2,95.25 203.2,92.71 RN5.4 203.2,90.17 203.2,84.45 J1.J
BUS_WP_STATUS_L
  Top 0.508: RN1.7 210.82,95.25 210.82,92.71 RN5.7 210.82,90.17 210.82,84.45 J1.R
BUS_WRITE_CK
  Top 0.508: RN2.6 231.14,95.25 231.14,92.71 RN6.6 231.14,90.17 231.14,84.45 J1.JJ
BUS_WRITE_GATE_L  (via drill 0.61)
  Top 0.508: v140.97,137.79 151.13,127.64 v151.13,125.09 | v219.07,100.97 222.88,97.16 RN2.9 223.52,95.25 223.52,92.71 RN6.9 223.52,90.17 223.52,84.45 J1.BB
  Bottom 0.508: v140.97,137.79 100.33,137.79 100.33,140.34 97.79,142.88 31.11,142.88 28.57,140.34 E9.13 | v151.13,125.09 154.94,121.28 181.61,121.28 201.93,100.97 v219.07,100.97
CA_SW_1
  Top 0.508: E26.9 121.92,105.41 124.46,107.95 124.46,108.58 R45.2
  Bottom 0.508: CYL1.3 120.65,109.86 121.28,109.22 123.83,109.22 R45.2
CA_SW_2
  Top 0.508: E26.12 113.67,104.78 109.86,108.58 109.86,109.22 R44.2
  Bottom 0.508: R44.2 108.58,109.22 107.95,109.86 105.41,109.86 CYL2.3
CA_SW_4  (via drill 0.61)
  Top 0.508: v95.25,57.78 93.98,59.05 93.98,108.58 R43.2
  Bottom 0.508: v95.25,57.78 133.99,57.78 136.53,60.33 E27.9 | CYL4.3 90.17,109.86 90.81,109.22 93.34,109.22 R43.2
CA_SW_8  (via drill 0.61)
  Top 0.508: v124.46,66.04 128.91,61.59 E27.12 | v106.68,66.67 106.68,94.61 100.33,100.97 v100.33,106.05
  Bottom 0.508: CYL8.3 74.93,109.86 77.47,109.86 78.11,109.22 R42.2 79.38,109.22 80.64,107.95 98.42,107.95 v100.33,106.05 | v124.46,66.04 123.83,66.67 v106.68,66.67
CA_SW_16  (via drill 0.61)
  Top 0.508: v111.76,64.14 111.76,62.23 E28.9 | v78.74,67.31 76.2,69.85 76.2,104.78 69.22,111.76 69.22,115.57 68.58,116.2 63.5,116.2 63.5,109.86 R41.2
  Bottom 0.508: R41.2 62.87,109.22 62.23,109.86 59.69,109.86 CYL16.3 | v111.76,64.14 92.71,64.14 89.53,67.31 v78.74,67.31
CA_SW_32  (via drill 0.61)
  Top 0.508: v104.14,76.2 104.14,62.23 E28.12 | v53.34,78.11 49.53,81.92 49.53,107.31 48.26,108.58 R40.2
  Bottom 0.508: R40.2 47.62,109.22 46.99,109.86 44.45,109.86 CYL32.3 | v104.14,76.2 65.41,76.2 63.5,78.11 v53.34,78.11
CA_SW_64  (via drill 0.61)
  Top 0.508: v91.44,50.8 91.44,44.45 E29.9 | v41.91,50.8 40.01,52.7 40.01,92.08 33.02,99.06 33.02,108.58 R39.2
  Bottom 0.508: v41.91,50.8 v91.44,50.8 | CYL64.3 29.21,109.86 29.84,109.22 32.38,109.22 R39.2
CA_SW_128  (via drill 0.61)
  Top 0.508: v83.82,56.52 83.82,44.45 E29.12 | v77.47,60.33 74.93,62.87 v74.93,100.97
  Bottom 0.508: CYL128.3 13.97,109.86 16.51,109.86 17.14,109.22 R38.2 18.41,109.22 26.67,100.97 v74.93,100.97 | v83.82,56.52 80.01,60.33 v77.47,60.33
CLOCK_H  (via drill 0.61)
  Top 0.508: 152.4,130.81 153.03,130.18 v153.03,128.91 | 152.4,130.81 E8.1 152.4,130.81 | v156.21,100.97 156.21,122.56 152.4,126.36 152.4,130.81
  Bottom 0.508: E7.10 146.69,104.78 145.41,106.05 144.15,106.05 142.88,104.78 E7.12 141.6,104.78 140.34,106.05 139.06,106.05 138.43,105.41 138.43,100.97 v156.21,100.97 | v153.03,128.91 159.38,128.91 161.93,131.44 E8.5
CONSTANT_WRITE_L  (via drill 0.61)
  Top 0.508: v144.15,121.92 147.32,118.75 147.32,116.2 148.59,114.94 CONSTANT_WRITE.2
  Bottom 0.508: v144.15,121.92 128.91,121.92 127,123.83 96.52,123.83 94.61,125.73 49.53,125.73 49.53,133.35 50.16,133.99 56.52,133.99 57.78,132.72 E11.4
DATA_BITS
  Bottom 0.508: BIT0.3 196.85,109.86 209.55,109.86 BIT1.3 212.09,109.86 212.72,109.22 220.34,109.22 R7.1 221.62,109.22 222.25,109.86 224.79,109.86 BIT2.3 227.33,110.49 240.03,110.49 BIT3.3
DC_ERASE  (via drill 0.61)
  Top 0.508: v123.19,114.94 123.19,116.2 118.11,116.2 116.84,117.47 116.84,118.75 118.11,120.02 118.11,142.88 49.53,142.88 46.99,140.34 41.27,140.34 E9.8
  Bottom 0.508: v123.19,114.94 124.46,113.67 147.32,113.67 148.59,112.39 162.56,112.39 163.83,113.67 DC_ERASE.2
FWD_L  (via drill 0.61)
  Top 0.508: v53.34,80.64 53.34,83.19 50.8,85.72 R36.1 | v109.22,20.95 109.22,19.05 E17.9 | v144.78,22.23 147.32,19.68 147.32,19.05 E16.9 | v100.33,80.01 102.87,77.47 v102.87,68.58 | v112.39,65.41 116.2,61.59 v116.2,22.23
  Bottom 0.508: v53.34,80.64 57.15,80.64 FWD/REV.3 59.69,80.01 v100.33,80.01 | v109.22,20.95 110.49,22.23 v116.2,22.23 v144.78,22.23 | v102.87,68.58 106.05,65.41 v112.39,65.41
GND  (via drill 0.61)
  Top 0.508: C53.2 236.22,104.78 238.76,107.31 238.76,116.2 240.03,117.47 BIT3.1 242.57,118.75 242.57,127 246.38,130.81 E1.7 | E8.8 170.18,133.35 170.18,138.43 E8.9 | C2.2 202.56,132.08 196.22,132.08 E4.7 195.58,130.81 198.12,128.27 198.12,127.64 R14.1 198.12,126.36 198.12,125.09 R15.1 198.12,123.83 198.12,120.02 196.85,118.75 BIT0.1 | C1.2 228.6,131.44 227.33,130.18 227.33,118.75 BIT2.1 | RN8.1 247.01,60.96 248.28,60.96 C41.2 248.92,61.59 v248.92,66.67 | 245.11,12.7 243.84,13.97 243.84,16.51 E12.9 | 245.11,12.7 246.38,11.43 E12.7 | E14.8 203.2,11.43 203.2,16.51 E14.9 203.2,19.05 203.2,19.68 198.12,24.77 R31.1 | E13.4 220.34,10.79 219.07,12.06 210.82,12.06 210.82,10.79 C13.2 | 245.11,12.7 245.11,43.81 243.84,45.09 R23.1 | E5.2 168.28,95.89 169.54,95.89 E5.3 | WRITE_BUTTON.2 166.37,84.45 167.64,85.72 167.64,95.25 E5.2 | E7.7 152.4,95.25 152.4,81.92 151.13,80.64 HEAD.3 151.13,79.38 151.76,78.74 151.76,71.75 C61.- 153.03,70.48 157.48,70.48 161.29,66.67 161.29,59.05 162.56,57.78 162.56,53.98 C3.2 162.56,52.7 162.56,38.73 165.1,36.2 C30.2 165.1,34.92 165.1,19.05 E15.12 | DC_ERASE.3 166.37,109.86 166.37,99.06 167.64,97.79 E5.2 | C43.2 245.75,91.44 244.47,91.44 RN6.1 | C42.2 193.68,91.44 194.94,91.44 RN5.1 195.58,90.17 195.58,84.45 J1.B 195.58,83.19 195.58,81.92 J1.A 196.22,81.28 197.49,81.28 J1.C 198.75,81.28 200.03,81.28 J1.E 201.29,81.28 202.56,81.28 J1.H 203.84,81.28 205.1,81.28 J1.K 206.38,81.28 207.65,81.28 J1.M 208.91,81.28 210.19,81.28 J1.P 211.46,81.28 212.72,81.28 J1.S 214,81.28 215.26,81.28 J1.U 216.53,81.28 217.81,81.28 J1.W 219.07,81.28 220.34,81.28 J1.Y 221.62,81.28 222.88,81.28 J1.AA 224.16,81.28 225.43,81.28 J1.CC 226.69,81.28 227.97,81.28 J1.EE 229.24,81.28 230.5,81.28 J1.HH 231.78,81.28 233.04,81.28 J1.KK 234.31,81.28 235.59,81.28 J1.MM 236.85,81.28 238.12,81.28 J1.PP 239.4,81.28 240.66,81.28 J1.SS
  Top 0.508: J1.UU 243.21,81.28 241.94,81.28 J1.SS | C40.2 191.13,60.96 192.41,60.96 RN7.1 | v187.96,61.59 187.96,67.94 C52.- | J2.B 196.22,71.12 197.49,71.12 J2.D 198.75,71.12 200.03,71.12 J2.F 201.29,71.12 202.56,71.12 J2.J 203.84,71.12 205.1,71.12 J2.L 206.38,71.12 207.65,71.12 J2.N 208.91,71.12 210.19,71.12 J2.R 211.46,71.12 212.72,71.12 J2.T 214,71.12 215.26,71.12 J2.V 216.53,71.12 217.81,71.12 J2.X 219.07,71.12 220.34,71.12 J2.Z 221.62,71.12 222.88,71.12 J2.BB 224.16,71.12 225.43,71.12 J2.DD 226.69,71.12 227.97,71.12 J2.FF 229.24,71.12 230.5,71.12 J2.JJ 231.78,71.12 233.04,71.12 J2.LL 234.31,71.12 235.59,71.12 J2.NN 236.85,71.12 238.12,71.12 J2.RR 239.4,71.12 240.66,71.12 J2.TT | J2.VV 243.21,71.12 241.94,71.12 J2.TT | J1.SS 241.3,80.64 241.3,71.75 J2.TT | POWER.1 117.47,86.36 120.02,86.36 120.65,87 120.65,91.44 124.46,95.25 E26.7 124.46,97.79 120.65,101.6 120.65,108.58 121.92,109.86 121.92,112.39 120.65,113.67 CYL1.2 | C28.2 96.52,53.98 96.52,59.05 95.25,60.33 v95.25,62.87 95.25,82.55 98.42,85.72 POWER_ON.B | E24.13 104.14,138.43 99.06,133.35 99.06,132.72 C24.2 | E24.7 116.84,133.35 114.3,135.89 114.3,138.43 E24.9 113.67,139.06 112.39,139.06 E24.10 111.12,139.06 111.12,137.79 108.58,137.79 107.31,139.06 E24.12 | E9.2 28.57,131.44 29.84,131.44 E9.3 | E9.5 36.2,131.44 37.47,131.44 E9.6 38.73,131.44 40.01,131.44 E9.7 41.27,132.08 47.62,132.08 C11.2 | 71.12,132.08 73.03,132.08 C10.2 | 71.12,132.08 66.67,132.08 E11.7 | 22.86,113.67 26.67,113.67 CYL64.2 | 22.86,113.67 13.97,113.67 CYL128.2 | 45.72,113.67 44.45,113.67 CYL32.2 | 45.72,113.67 52.7,113.67
  Top 0.508: 52.7,113.67 57.15,113.67 CYL16.2 | 71.12,132.08 71.12,116.2 72.39,114.94 CYL8.2 | 45.72,113.67 45.72,85.72 44.45,84.45 RTZ.2 | 22.86,113.67 22.86,131.44 C9.2 | 52.7,113.67 52.7,97.16 C60.- | E10.7 91.44,130.81 91.44,116.2 90.17,114.94 CYL4.2 | E19.15 45.72,19.05 48.26,21.59 48.26,34.29 E22.4 | E33.4 38.1,59.69 38.1,55.88 36.2,53.98 C68.- 36.2,52.7 36.83,52.07 36.83,37.47 38.1,36.2 C22.2 38.1,34.92 38.1,13.34 40.64,10.79 C19.2 | C34.2 48.26,56.52 45.72,59.05 45.72,60.33 C21.2 | E20.15 17.78,16.51 15.24,13.97 15.24,11.43 E20.1 | C31.2 144.78,36.2 139.7,41.27 139.7,52.07 E27.7 | E3.8 182.88,52.07 182.88,37.47 184.15,36.2 SECTOR.12 184.78,36.2 186.06,34.92 186.06,33.66 SECTOR.11 186.06,33.02 186.06,31.75 182.88,28.57 C38.2 | C16.2 132.08,9.53 133.99,7.62 149.22,7.62 149.22,9.53 E16.7 | E14.1 184.78,10.16 183.51,10.16 C14.2 | E15.13 163.19,17.14 164.47,17.14 E15.12 | E15.10 170.81,17.14 172.09,17.14 E15.9 | 173.35,13.34 172.72,13.97 172.72,16.51 E15.9 | 173.35,13.34 175.26,11.43 E15.7 | 173.35,13.34 170.81,10.79 E15.5 | E15.12 165.1,16.51 167.64,13.97 167.64,11.43 E15.4 | E30.4 175.26,34.29 175.26,21.59 172.72,19.05 E15.9 | E18.7 87,10.16 93.34,10.16 C17.2 | C18.2 67.94,10.16 61.59,10.16 E19.8 60.96,11.43 60.96,13.97 58.42,16.51 E19.10 | E17.7 111.76,11.43 113.67,13.34 113.67,34.92 E32.4 114.3,36.83 113.03,38.1 113.03,44.45 114.3,45.72 114.3,52.07 E28.7 | FWD/REV.2 59.69,84.45 62.23,84.45 62.23,74.93 57.15,69.85 57.15,63.5 55.88,62.23 E21.4
  Bottom 0.508: E8.8 170.81,132.08 177.16,132.08 C4.2 177.8,132.72 179.07,133.99 193.68,133.99 194.94,132.72 E4.7 | E2.7 221.62,132.08 227.97,132.08 C1.2 | BIT0.1 196.85,117.47 209.55,117.47 BIT1.1 212.09,117.47 224.79,117.47 BIT2.1 227.33,117.47 240.03,117.47 BIT3.1 | C36.2 231.78,40.64 233.04,41.91 239.4,41.91 243.21,45.72 R23.1 243.84,46.35 250.19,52.7 250.19,60.33 248.92,60.33 C41.2 | R70.1 208.91,58.42 209.55,59.05 217.17,59.05 217.81,59.69 222.25,59.69 223.52,58.42 230.5,58.42 R148.1 231.78,58.42 243.84,58.42 245.75,60.33 RN8.1 | E13.4 221.62,10.16 227.97,10.16 C12.2 228.6,10.79 229.87,12.06 244.47,12.06 245.75,10.79 E12.7 | D5.A 209.55,22.86 205.1,18.41 203.84,18.41 E14.9 | C13.2 210.19,10.16 203.84,10.16 E14.8 | CONSTANT_WRITE.3 151.13,109.86 163.83,109.86 DC_ERASE.3 | WRITE_BUTTON.2 166.37,83.19 174.62,83.19 C45.+ 175.9,83.19 177.16,81.92 195.58,81.92 J1.A | E7.7 153.03,96.52 161.93,96.52 C5.2 162.56,95.89 163.83,94.61 172.09,94.61 | 172.09,94.61 178.44,94.61 179.71,95.89 E5.7 | 172.09,94.61 170.81,95.89 E5.3 | RN6.1 243.21,90.81 241.94,90.81 RN6.2 241.3,92.71 240.66,92.71 239.4,93.98 C39.2 238.76,94.61 232.41,94.61 232.41,99.69 236.22,103.5 C53.2 | C43.2 246.38,90.81 246.38,81.92 243.84,81.92 J1.UU | v187.96,61.59 189.23,61.59 189.87,60.96 C40.2 | C44.- 180.97,67.94 187.32,67.94 C52.- 188.59,69.22 193.04,69.22 194.94,71.12 J2.B | v248.92,66.67 244.47,71.12 J2.VV | E26.7 125.09,96.52 133.99,96.52 C7.2 | v95.25,62.87 87,62.87 C67.- | POWER.1 111.12,85.72 99.69,85.72 POWER_ON.B | E24.13 104.78,139.06 106.05,139.06 E24.12 | E10.7 92.08,132.08 98.42,132.08 C24.2
  Bottom 0.508: C8.2 149.22,132.08 142.88,132.08 E6.7 141.6,131.44 140.34,130.18 128.91,130.18 127.64,131.44 E6.1 126.36,132.08 125.09,132.08 C6.2 123.83,132.08 117.47,132.08 E24.7 | C26.2 106.05,96.52 53.98,96.52 C60.- | C9.2 22.86,131.44 24.13,130.18 26.04,130.18 27.3,131.44 E9.2 | E9.3 31.11,132.72 32.38,133.99 33.66,133.99 34.92,132.72 E9.5 | RTZ.2 44.45,83.19 57.15,83.19 FWD/REV.2 | CYL32.2 41.91,113.67 29.21,113.67 CYL64.2 | CYL16.2 59.69,113.67 72.39,113.67 CYL8.2 74.93,113.67 87.63,113.67 CYL4.2 90.17,113.67 102.87,113.67 CYL2.2 105.41,113.67 118.11,113.67 CYL1.2 | 59.05,34.92 59.05,36.2 62.23,39.37 DRIVE.C1 | 59.05,34.92 48.9,34.92 E22.4 47.62,36.2 46.35,37.47 39.37,37.47 38.1,36.2 C22.2 37.47,35.56 31.11,35.56 E23.7 29.84,36.2 28.57,37.47 13.97,37.47 12.7,36.2 C23.2 | 59.05,34.92 62.87,34.92 63.5,35.56 75.56,35.56 C29.2 | E21.4 55.24,60.33 50.8,55.88 48.9,55.88 C34.2 | C21.2 45.09,60.96 38.73,60.96 E33.4 37.47,61.59 34.92,64.14 31.75,64.14 27.94,67.94 C33.2 | C20.2 13.34,10.16 14.61,10.16 E20.1 15.88,9.53 17.14,8.26 31.11,8.26 32.38,9.53 E20.8 33.66,10.16 40.01,10.16 C19.2 40.64,10.79 41.91,12.06 59.05,12.06 60.33,10.79 E19.8 | E27.7 140.34,53.34 161.93,53.34 C3.2 | E30.4 175.9,36.2 184.15,36.2 SECTOR.12 | E16.7 150.5,10.16 156.84,10.16 C15.2 157.48,9.53 157.48,6.99 164.47,6.99 167,9.53 E15.4 168.28,9.53 169.54,9.53 E15.5 | E31.4 155.57,35.56 164.47,35.56 C30.2 | C14.2 182.25,10.16 175.9,10.16 E15.7 | E18.7 85.72,10.79 84.45,12.06 69.85,12.06 68.58,10.79 C18.2 | E29.7 94.61,35.56 103.5,35.56 C32.2 104.14,36.2 105.41,37.47 116.2,37.47 | E28.7 114.94,53.34 121.28,53.34 C27.2
  Bottom 0.508: 116.2,37.47 123.83,37.47 125.73,39.37 FUNCTION.C1 126.36,39.37 129.54,39.37 130.18,38.73 133.35,38.73 136.53,35.56 144.15,35.56 C31.2 | 116.2,37.47 114.94,36.2 E32.4 | C17.2 93.98,10.79 95.25,12.06 109.86,12.06 111.12,10.79 E17.7
HEAD_SELECT_L
  Top 0.508: RN1.10 218.44,95.25 218.44,92.71 RN5.10 218.44,90.17 218.44,84.45 J1.X
  Bottom 0.508: HEAD.2 151.13,84.45 154.31,87.63 161.93,87.63 163.83,89.53 190.5,89.53 194.31,85.72 215.9,85.72 217.81,83.82 J1.X
N$1  (via drill 0.61)
  Top 0.508: v233.68,6.99 216.53,6.99 214,9.53 E13.1
  Bottom 0.508: v233.68,6.99 234.95,8.26 241.94,8.26 243.21,9.53 E12.6
N$2  (via drill 0.61)
  Top 0.508: v129.54,136.53 128.27,135.25 v128.27,118.11 | v144.15,117.47 146.05,115.57 146.05,101.6 149.86,97.79 E7.6
  Bottom 0.508: v129.54,136.53 41.27,136.53 38.73,139.06 E9.9 | v128.27,118.11 128.91,117.47 v144.15,117.47
N$3
  Top 0.508: E11.13 53.98,139.06 55.24,139.06 E11.12
  Bottom 0.508: 80.64,137.79 79.38,139.06 E10.13 | 80.64,137.79 89.53,137.79 90.81,139.06 E10.8 | 80.64,137.79 57.78,137.79 56.52,139.06 E11.12
N$4
  Top 0.508: E10.11 84.45,139.06 85.72,139.06 E10.10
N$5  (via drill 0.61)
  Top 0.508: R10.1 215.9,144.15 215.9,140.97 E2.10 215.9,138.43 213.36,135.89 213.36,133.35 E2.4 213.36,130.81 213.36,125.09 v190.5,102.23
  Bottom 0.508: v190.5,102.23 177.16,102.23 175.9,103.5 E5.10
N$6
  Top 0.508: E7.4 144.78,97.79 144.78,102.87 E7.11
N$7
  Top 0.508: E7.5 147.96,95.89 149.22,94.61 151.13,94.61 151.13,101.6 152.4,102.87 E7.8
N$8
  Top 0.508: E11.3 56.52,132.72 62.87,139.06 E11.9
N$9  (via drill 0.61)
  Top 0.508: v152.4,108.58 152.4,107.95 149.86,105.41 E7.9 | v175.26,108.58 189.23,122.56 189.23,135.89 191.77,138.43 191.77,140.97 192.41,141.6 195.58,141.6 195.58,140.97 E4.8
  Bottom 0.508: v152.4,108.58 v175.26,108.58
N$10
  Top 0.508: R20.1 238.76,38.73 238.76,40.01 C36.1
  Bottom 0.508: E13.3 219.07,10.79 221.62,13.34 244.47,13.34 248.92,17.78 248.92,39.37 242.57,39.37 Q1.E 241.3,39.37 240.66,39.37 239.4,38.1 R20.1
N$11
  Bottom 0.508: E8.14 158.12,139.06 161.93,135.25 172.72,135.25 C63.2
N$12
  Bottom 0.508: E8.6 165.1,130.81 161.29,127 160.66,127 C62.2
N$13
  Top 0.508: C63.1 172.09,142.24 168.28,146.05 168.28,146.69 R9.E 166.37,147.32 163.83,144.78 R9.S
  Bottom 0.508: E8.15 155.57,140.34 160.02,144.78 161.29,144.78 R9.S
N$14
  Top 0.508: R8.1 167.64,125.09 167.64,126.36 C62.1 167.64,127.64 167.64,130.81 E8.7
N$15
  Top 0.508: E9.12 31.11,140.34 41.27,150.5 121.92,150.5 121.92,145.41 125.73,141.6 133.35,141.6 133.35,138.43 138.43,133.35 138.43,110.49 143.51,105.41 143.51,99.06 142.24,97.79 E7.3
N$16
  Top 0.508: R21.1 243.84,36.2 243.84,37.47 Q1.B1
N$17
  Top 0.508: Q1.B2 243.84,41.27 243.84,42.55 R22.2
N$18
  Top 0.508: R23.2 233.68,45.09 233.68,43.81 R22.1 233.68,42.55 232.41,41.27 232.41,20.32 | 232.41,20.32 231.14,21.59 231.14,22.23 C37.2 | 232.41,20.32 233.68,19.05 E12.13
N$19  (via drill 0.61)
  Top 0.508: E14.2 188.59,9.53 189.87,8.26 199.39,8.26 v199.39,14.61 199.39,15.24 200.66,16.51 E14.10 | v112.39,24.77 v106.68,30.48 | v177.16,20.32 178.44,19.05 v178.44,12.06
  Bottom 0.508: C37.1 238.12,22.86 236.22,22.86 236.22,19.05 E12.12 235.59,17.14 233.04,14.61 v199.39,14.61 | v106.68,30.48 45.72,30.48 41.27,34.92 E22.1 | v112.39,24.77 144.78,24.77 147.32,22.23 175.26,22.23 v177.16,20.32 | v178.44,12.06 186.06,12.06 187.32,10.79 E14.2
N$20
  Top 0.508: E17.1 97.16,9.53 102.87,3.81 108.58,3.81 108.58,9.53 E17.6
N$21  (via drill 0.61)
  Top 0.508: E17.4 103.5,9.53 102.23,9.53 E17.3 101.6,11.43 100.33,12.7 v100.33,71.75 | v52.07,73.03 52.07,66.04 48.26,62.23 E21.1
  Bottom 0.508: v52.07,73.03 57.78,73.03 59.05,71.75 v100.33,71.75
N$22
  Top 0.508: C35.1 187.96,22.23 187.96,19.05 E14.15 188.59,18.41 188.59,19.05 194.94,25.4 R25.1
N$23
  Top 0.508: E14.14 191.13,18.41 194.94,22.23 194.94,22.86 C35.2
N$24
  Top 0.508: E14.7 200.66,8.89 200.66,5.71 R28.1 201.29,5.08 204.47,8.26 204.47,20.95 205.74,22.23 C25.1
N$25
  Top 0.508: E14.6 198.12,11.43 196.85,12.7 196.85,20.95 198.12,22.23 C25.2
N$26  (via drill 0.61)
  Top 0.508: v50.8,14.61 50.8,16.51 E19.13
  Bottom 0.508: v50.8,14.61 27.3,14.61 23.5,10.79 E20.4
N$27
  Top 0.508: E20.5 26.04,9.53 28.57,6.99 49.53,6.99 49.53,11.43 53.34,15.24 53.34,16.51 E19.12
N$28  (via drill 0.61)
  Top 0.508: v83.82,13.97 85.09,15.24 v85.09,27.3 | v120.02,29.84 128.91,20.95 128.91,17.78 130.81,15.88 140.97,15.88 140.97,19.05 141.6,19.68 146.05,19.68 146.05,12.7 147.32,11.43 E16.6
  Bottom 0.508: v83.82,13.97 70.48,13.97 64.77,8.26 55.24,8.26 53.98,9.53 E19.5 | v85.09,27.3 92.08,27.3 93.98,29.21 111.12,29.21 111.76,29.84 v120.02,29.84
N$29  (via drill 0.61)
  Top 0.508: v146.05,125.09 146.05,125.73 140.34,131.44 E6.6 | v151.13,121.92 154.94,118.11 154.94,75.56 167.64,62.87 167.64,62.23 E3.15
  Bottom 0.508: v146.05,125.09 149.22,121.92 v151.13,121.92
N$30
  Bottom 0.508: RUN.2 29.21,83.82 38.73,83.82 41.91,87 RTZ.1
N$31  (via drill 0.61)
  Top 0.508: v149.86,64.14 149.86,66.67 140.97,75.56 140.97,105.41 135.89,110.49 135.89,134.62 132.08,138.43 E6.12
  Bottom 0.508: v149.86,64.14 151.13,62.87 168.28,62.87 169.54,61.59 E3.14
N$32  (via drill 0.61)
  Top 0.508: v166.37,51.44 166.37,62.87 153.67,75.56 153.67,117.47 147.32,123.83 147.32,129.54 137.79,139.06 E6.10
  Bottom 0.508: v166.37,51.44 173.35,51.44 173.99,52.07 173.99,59.69 172.72,59.69 E3.13
N$33
  Top 0.508: E6.8 142.88,140.34 151.76,149.22 173.99,149.22 173.99,85.09 173.35,84.45 173.35,66.04 175.26,64.14 175.26,62.23 E3.12
N$34
  Top 0.508: E6.2 130.18,131.44 131.44,131.44 E6.3
N$35  (via drill 0.61)
  Top 0.508: v74.93,3.81 64.77,3.81 59.69,8.89 59.69,12.06 57.78,12.06 57.15,11.43 57.15,5.71 55.24,5.71 51.44,9.53 E19.4 | v113.03,3.81 116.2,6.99 v116.2,16.51 | v130.18,18.41 136.53,24.77 149.86,24.77 149.86,19.05 E16.8
  Bottom 0.508: v74.93,3.81 v113.03,3.81 | v116.2,16.51 118.11,18.41 v130.18,18.41
N$36  (via drill 0.61)
  Top 0.508: E10.4 84.45,131.44 85.72,131.44 E10.5 87,132.72 v89.53,135.25 | v131.44,135.25 133.99,132.72 E6.4
  Bottom 0.508: E10.1 76.83,131.44 78.11,131.44 E10.2 79.38,131.44 80.64,130.18 81.92,130.18 83.19,131.44 E10.4 | v131.44,135.25 v89.53,135.25
N$37
  Top 0.508: R1.1 71.12,79.38 71.12,83.19 ADDR_INV.A
N$38
  Top 0.508: R2.1 86.36,79.38 86.36,83.19 SEEK_INC.A
N$39
  Top 0.508: R3.1 99.06,79.38 99.06,83.19 POWER_ON.A
N$40  (via drill 0.61)
  Top 0.508: v52.07,21.59 55.88,21.59 55.88,19.05 E19.11 | v110.49,24.77 110.49,20.32 111.76,19.05 E17.8
  Bottom 0.508: 50.16,21.59 v52.07,21.59 | 50.16,21.59 31.75,21.59 28.57,18.41 E20.11 | v110.49,24.77 104.78,24.77 100.97,20.95 69.85,20.95 67.94,22.86 55.24,22.86 53.98,24.13 52.7,24.13 50.16,21.59
N$41
  Bottom 0.508: 46.35,15.88 22.23,15.88 20.95,17.14 E20.14 | 46.35,15.88 47.62,17.14 E19.14 | 46.35,15.88 51.44,15.88 52.07,15.24 137.16,15.24 139.06,17.14 E16.12
N$42  (via drill 0.61)
  Top 0.508: R29.1 185.42,27.3 182.88,24.77 182.88,20.95 C38.1 | v209.55,29.21 215.26,34.92 E25.2
  Bottom 0.508: v209.55,29.21 191.13,29.21 189.87,27.94 186.06,27.94 R29.1
N$43
  Top 0.508: R29.2 196.22,27.94 197.49,27.94 R30.2 | E25.6 218.44,41.91 217.17,40.64 217.17,32.38 210.82,26.04 R32.1
  Bottom 0.508: R32.1 210.19,25.4 208.91,26.67 200.03,26.67 198.75,27.94 R30.2
N$44
  Top 0.508: R30.1 208.28,27.3 208.28,26.04 R31.2 208.28,24.77 208.28,24.13 211.46,24.13 218.44,31.11 218.44,34.29 E25.3
N$46  (via drill 0.61)
  Top 0.508: v34.29,88.9 34.29,83.19 24.13,73.03 24.13,41.91 18.41,36.2 E23.2 | v117.47,100.97 120.65,97.79 v120.65,94.61 | v138.43,90.17 139.7,88.9 139.7,75.56 144.15,71.12 v144.15,59.05 | v160.66,57.78 161.29,57.15 161.29,12.7 162.56,11.43 E15.2
  Bottom 0.508: E15.2 163.19,10.79 164.47,12.06 170.81,12.06 171.45,11.43 171.45,6.99 230.5,6.99 233.04,9.53 E12.2 | v34.29,88.9 45.09,99.69 93.34,99.69 94.61,100.97 v117.47,100.97 | v120.65,94.61 125.09,90.17 v138.43,90.17 | v144.15,59.05 145.41,57.78 v160.66,57.78
N$47
  Bottom 0.508: E15.1 160.66,10.79 163.19,13.34 189.87,13.34 192.41,10.79 E14.4
N$48
  Top 0.508: D3.A 60.96,59.69 63.5,62.23 63.5,67.31 D2.C
N$53
  Top 0.508: D4.A 58.42,59.69 60.96,62.23 60.96,67.31 D3.C
N$55
  Top 0.508: E13.6 218.44,16.51 226.69,8.26 234.95,8.26 234.95,11.43 235.59,12.06 238.76,12.06 238.76,11.43 E12.4
N$57  (via drill 0.61)
  Top 0.508: v195.58,13.34 195.58,16.51 E14.12 195.58,19.05 v195.58,20.95 | v211.46,13.34 215.26,17.14 E13.7 | 13.97,33.02 15.24,34.29 E23.1 | 13.97,33.02 13.97,8.89 21.59,1.27 76.2,1.27 76.2,8.89 E18.3 | v178.44,21.59 176.53,23.5 v176.53,27.94 | v143.51,29.84 137.16,36.2 137.16,50.8 135.89,52.07 135.89,62.23 v127,71.12 | v21.59,74.3 13.97,66.67 13.97,33.02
